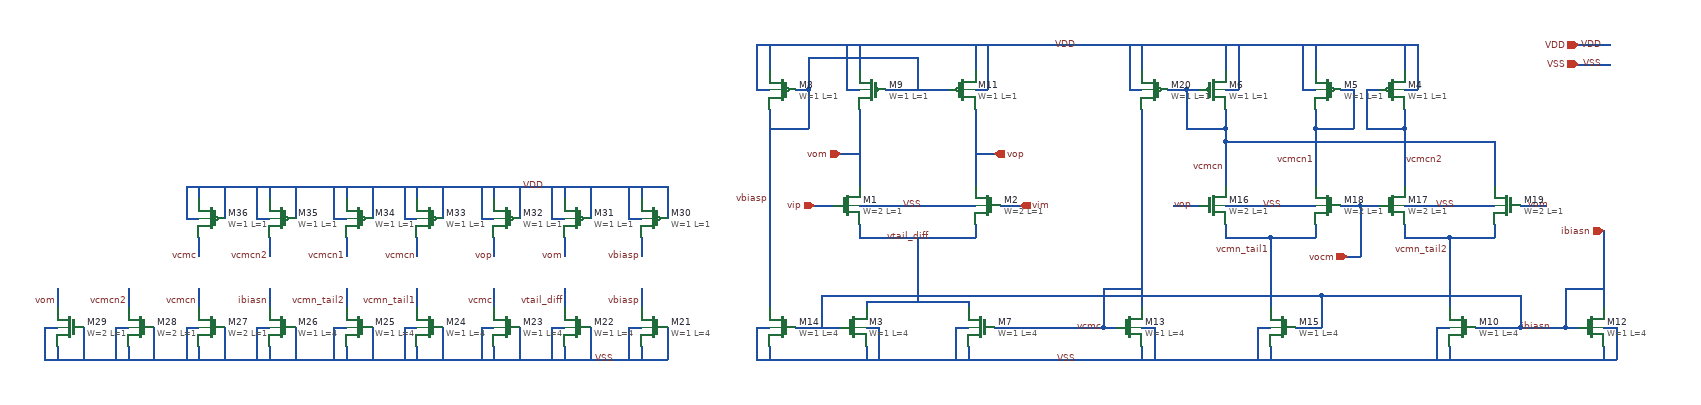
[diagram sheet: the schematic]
v {xschem version=2.9.9 file_version=1.2 

* Copyright 2020 Stefan Frederik Schippers
* 
* Licensed under the Apache License, Version 2.0 (the "License");
* you may not use this file except in compliance with the License.
* You may obtain a copy of the License at
*
*     https://www.apache.org/licenses/LICENSE-2.0
*
* Unless required by applicable law or agreed to in writing, software
* distributed under the License is distributed on an "AS IS" BASIS,
* WITHOUT WARRANTIES OR CONDITIONS OF ANY KIND, either express or implied.
* See the License for the specific language governing permissions and
* limitations under the License.

}
G {}
K {}
V {}
S {}
E {}
N -110 -220 -90 -220 { lab=VSS}
N -90 -220 -90 -170 { lab=VSS}
N 30 -220 50 -220 { lab=VSS}
N 30 -220 30 -170 { lab=VSS}
N -110 -260 -110 -250 { lab=vtail_diff}
N -110 -260 50 -260 { lab=vtail_diff}
N 50 -260 50 -250 { lab=vtail_diff}
N 50 -190 50 -170 { lab=VSS}
N -110 -190 -110 -170 { lab=VSS}
N -10 -410 60 -410 { lab=VSS}
N -120 -380 -120 -360 { lab=vtail_diff}
N -120 -360 60 -360 { lab=vtail_diff}
N 60 -380 60 -360 { lab=vtail_diff}
N 660 -410 690 -410 { lab=vocm}
N 520 -190 520 -170 { lab=VSS}
N 800 -190 800 -170 { lab=VSS}
N 450 -380 450 -360 { lab=vcmn_tail1}
N 520 -360 590 -360 { lab=vcmn_tail1}
N 590 -380 590 -360 { lab=vcmn_tail1}
N 730 -380 730 -360 { lab=vcmn_tail2}
N 800 -360 870 -360 { lab=vcmn_tail2}
N 870 -380 870 -360 { lab=vcmn_tail2}
N 670 -590 690 -590 { lab=vcmcn2}
N 670 -590 670 -530 { lab=vcmcn2}
N 670 -530 730 -530 { lab=vcmcn2}
N 390 -590 410 -590 { lab=vcmcn}
N 390 -590 390 -530 { lab=vcmcn}
N 390 -530 450 -530 { lab=vcmcn}
N 450 -510 450 -440 { lab=vcmcn}
N 450 -590 470 -590 { lab=VDD}
N 730 -590 750 -590 { lab=VDD}
N 450 -410 590 -410 { lab=VSS}
N 730 -410 870 -410 { lab=VSS}
N 780 -220 800 -220 { lab=VSS}
N 780 -220 780 -170 { lab=VSS}
N 500 -220 520 -220 { lab=VSS}
N 500 -220 500 -170 { lab=VSS}
N 1040 -190 1040 -170 { lab=VSS}
N 1040 -220 1060 -220 { lab=VSS}
N 1060 -220 1060 -170 { lab=VSS}
N 980 -220 1000 -220 { lab=ibiasn}
N 560 -220 600 -220 { lab=ibiasn}
N 600 -270 600 -220 { lab=ibiasn}
N 600 -270 910 -270 { lab=ibiasn}
N 910 -270 910 -220 { lab=ibiasn}
N 910 -410 950 -410 { lab=vom}
N 750 -660 750 -590 { lab=VDD}
N 730 -660 730 -620 { lab=VDD}
N 470 -660 470 -590 { lab=VDD}
N 450 -660 450 -620 { lab=VDD}
N 1040 -270 1040 -250 { lab=ibiasn}
N 800 -360 800 -250 { lab=vcmn_tail2}
N 520 -360 520 -250 { lab=vcmn_tail1}
N 320 -190 320 -170 { lab=VSS}
N 320 -220 340 -220 { lab=VSS}
N 340 -220 340 -170 { lab=VSS}
N 300 -590 320 -590 { lab=VDD}
N 320 -660 320 -620 { lab=VDD}
N 300 -660 300 -590 { lab=VDD}
N 630 -590 650 -590 { lab=vcmcn1}
N 650 -590 650 -530 { lab=vcmcn1}
N 590 -530 650 -530 { lab=vcmcn1}
N 570 -590 590 -590 { lab=VDD}
N 570 -660 570 -590 { lab=VDD}
N 590 -660 590 -620 { lab=VDD}
N 320 -560 320 -450 { lab=vcmc}
N 360 -590 390 -590 { lab=vcmcn}
N 730 -530 730 -440 { lab=vcmcn2}
N 590 -530 590 -440 { lab=vcmcn1}
N 870 -510 870 -440 { lab=vcmcn}
N 450 -510 870 -510 { lab=vcmcn}
N 640 -330 660 -330 { lab=vocm}
N 660 -410 660 -330 { lab=vocm}
N 730 -560 730 -530 { lab=vcmcn2}
N 450 -560 450 -530 { lab=vcmcn}
N 1040 -370 1040 -270 { lab=ibiasn}
N 910 -220 980 -220 { lab=ibiasn}
N 840 -220 910 -220 { lab=ibiasn}
N 730 -360 800 -360 { lab=vcmn_tail2}
N 450 -360 520 -360 { lab=vcmn_tail1}
N 590 -560 590 -530 { lab=vcmcn1}
N 450 -530 450 -510 { lab=vcmcn}
N -50 -410 -10 -410 { lab=VSS}
N -120 -410 -50 -410 { lab=VSS}
N 630 -410 660 -410 { lab=vocm}
N -190 -410 -160 -410 { lab=vip}
N 100 -410 130 -410 { lab=vim}
N -30 -360 -30 -340 { lab=vtail_diff}
N -30 -280 -30 -260 { lab=vtail_diff}
N -170 -220 -150 -220 { lab=ibiasn}
N 320 -390 320 -250 { lab=vcmc}
N 260 -280 260 -220 { lab=vcmc}
N 260 -280 320 -280 { lab=vcmc}
N 980 -280 980 -220 { lab=ibiasn}
N 980 -280 1040 -280 { lab=ibiasn}
N 60 -660 60 -620 { lab=VDD}
N 60 -590 80 -590 { lab=VDD}
N 80 -660 80 -590 { lab=VDD}
N -120 -660 -120 -620 { lab=VDD}
N -140 -590 -120 -590 { lab=VDD}
N -140 -660 -140 -590 { lab=VDD}
N -120 -560 -120 -440 { lab=vom}
N 60 -560 60 -440 { lab=vop}
N -150 -490 -120 -490 { lab=vom}
N 60 -490 90 -490 { lab=vop}
N 370 -410 410 -410 { lab=vop}
N 260 -220 280 -220 { lab=vcmc}
N 90 -220 110 -220 { lab=vcmc}
N -260 -190 -260 -170 { lab=VSS}
N -280 -220 -260 -220 { lab=VSS}
N -280 -220 -280 -170 { lab=VSS}
N -260 -660 -260 -620 { lab=VDD}
N -280 -590 -260 -590 { lab=VDD}
N -280 -660 -280 -590 { lab=VDD}
N -280 -170 1060 -170 { lab=VSS}
N -260 -560 -260 -250 { lab=vbiasp}
N -220 -220 -170 -220 { lab=ibiasn}
N -180 -270 600 -270 { lab=ibiasn}
N -180 -270 -180 -220 { lab=ibiasn}
N -220 -590 -200 -590 { lab=vbiasp}
N -200 -590 -200 -530 { lab=vbiasp}
N -260 -530 -200 -530 { lab=vbiasp}
N -200 -640 -200 -590 { lab=vbiasp}
N -200 -640 -30 -640 { lab=vbiasp}
N -30 -640 -30 -590 { lab=vbiasp}
N -80 -590 20 -590 { lab=vbiasp}
N 110 -220 260 -220 { lab=vcmc}
N -280 -660 750 -660 { lab=VDD}
N 1000 -660 1050 -660 { lab=VDD}
N 1000 -630 1050 -630 { lab=VSS}
N -30 -340 -30 -280 { lab=vtail_diff}
N 320 -450 320 -390 { lab=vcmc}
N -460 -190 -460 -170 { lab=VSS}
N -480 -220 -460 -220 { lab=VSS}
N -480 -220 -480 -170 { lab=VSS}
N -420 -220 -420 -170 { lab=VSS}
N -460 -280 -460 -250 { lab=vbiasp}
N -580 -190 -580 -170 { lab=VSS}
N -600 -220 -580 -220 { lab=VSS}
N -600 -220 -600 -170 { lab=VSS}
N -540 -220 -540 -170 { lab=VSS}
N -580 -280 -580 -250 { lab=vtail_diff}
N -690 -190 -690 -170 { lab=VSS}
N -710 -220 -690 -220 { lab=VSS}
N -710 -220 -710 -170 { lab=VSS}
N -650 -220 -650 -170 { lab=VSS}
N -690 -280 -690 -250 { lab=vcmc}
N -810 -190 -810 -170 { lab=VSS}
N -830 -220 -810 -220 { lab=VSS}
N -830 -220 -830 -170 { lab=VSS}
N -770 -220 -770 -170 { lab=VSS}
N -810 -280 -810 -250 { lab=vcmn_tail1}
N -920 -190 -920 -170 { lab=VSS}
N -940 -220 -920 -220 { lab=VSS}
N -940 -220 -940 -170 { lab=VSS}
N -880 -220 -880 -170 { lab=VSS}
N -920 -280 -920 -250 { lab=vcmn_tail2}
N -1040 -190 -1040 -170 { lab=VSS}
N -1060 -220 -1040 -220 { lab=VSS}
N -1060 -220 -1060 -170 { lab=VSS}
N -1000 -220 -1000 -170 { lab=VSS}
N -1040 -280 -1040 -250 { lab=ibiasn}
N -1150 -190 -1150 -170 { lab=VSS}
N -1170 -220 -1150 -220 { lab=VSS}
N -1170 -220 -1170 -170 { lab=VSS}
N -1110 -220 -1110 -170 { lab=VSS}
N -1150 -280 -1150 -250 { lab=vcmcn}
N -1260 -190 -1260 -170 { lab=VSS}
N -1280 -220 -1260 -220 { lab=VSS}
N -1280 -220 -1280 -170 { lab=VSS}
N -1220 -220 -1220 -170 { lab=VSS}
N -1260 -280 -1260 -250 { lab=vcmcn2}
N -1370 -190 -1370 -170 { lab=VSS}
N -1390 -220 -1370 -220 { lab=VSS}
N -1390 -220 -1390 -170 { lab=VSS}
N -1330 -220 -1330 -170 { lab=VSS}
N -1370 -280 -1370 -250 { lab=vom}
N -1390 -170 -420 -170 { lab=VSS}
N -460 -360 -460 -330 { lab=vbiasp}
N -420 -440 -420 -390 { lab=#net1}
N -460 -440 -460 -420 { lab=#net1}
N -480 -390 -460 -390 { lab=#net1}
N -480 -440 -480 -390 { lab=#net1}
N -580 -360 -580 -330 { lab=vom}
N -540 -440 -540 -390 { lab=#net1}
N -580 -440 -580 -420 { lab=#net1}
N -600 -390 -580 -390 { lab=#net1}
N -600 -440 -600 -390 { lab=#net1}
N -690 -360 -690 -330 { lab=vop}
N -650 -440 -650 -390 { lab=#net1}
N -690 -440 -690 -420 { lab=#net1}
N -710 -390 -690 -390 { lab=#net1}
N -710 -440 -710 -390 { lab=#net1}
N -810 -360 -810 -330 { lab=vcmcn}
N -770 -440 -770 -390 { lab=#net1}
N -810 -440 -810 -420 { lab=#net1}
N -830 -390 -810 -390 { lab=#net1}
N -830 -440 -830 -390 { lab=#net1}
N -920 -360 -920 -330 { lab=vcmcn1}
N -880 -440 -880 -390 { lab=#net1}
N -920 -440 -920 -420 { lab=#net1}
N -940 -390 -920 -390 { lab=#net1}
N -940 -440 -940 -390 { lab=#net1}
N -1040 -360 -1040 -330 { lab=vcmcn2}
N -1000 -440 -1000 -390 { lab=#net1}
N -1040 -440 -1040 -420 { lab=#net1}
N -1060 -390 -1040 -390 { lab=#net1}
N -1060 -440 -1060 -390 { lab=#net1}
N -1150 -360 -1150 -330 { lab=vcmc}
N -1110 -440 -1110 -390 { lab=#net1}
N -1150 -440 -1150 -420 { lab=#net1}
N -1170 -390 -1150 -390 { lab=#net1}
N -1170 -440 -1170 -390 { lab=#net1}
N -1170 -440 -420 -440 { lab=#net1}
C {devices/title.sym} 160 -30 0 0 {name=l1 author="Nikhil Poole"}
C {devices/lab_wire.sym} -10 -360 0 0 {name=l17 sig_type=std_logic lab=vtail_diff}
C {sky130_fd_pr/nfet_01v8.sym} 820 -220 0 1 {name=M10
L=4
W=1
nf=1
mult=1
ad="'int((nf+1)/2) * W/nf * 0.29'" 
pd="'2*int((nf+1)/2) * (W/nf + 0.29)'"
as="'int((nf+2)/2) * W/nf * 0.29'" 
ps="'2*int((nf+2)/2) * (W/nf + 0.29)'"
nrd="'0.29 / W'" nrs="'0.29 / W'"
sa=0 sb=0 sd=0
model=nfet_01v8
spiceprefix=X
}
C {sky130_fd_pr/nfet_01v8.sym} 1020 -220 0 0 {name=M12
L=4
W=1
nf=1
mult=10
ad="'int((nf+1)/2) * W/nf * 0.29'" 
pd="'2*int((nf+1)/2) * (W/nf + 0.29)'"
as="'int((nf+2)/2) * W/nf * 0.29'" 
ps="'2*int((nf+2)/2) * (W/nf + 0.29)'"
nrd="'0.29 / W'" nrs="'0.29 / W'"
sa=0 sb=0 sd=0
model=nfet_01v8
spiceprefix=X
}
C {devices/lab_wire.sym} 960 -220 0 0 {name=l63 sig_type=std_logic lab=ibiasn}
C {devices/lab_wire.sym} 590 -480 0 0 {name=l64 sig_type=std_logic lab=vcmcn1}
C {devices/lab_wire.sym} 450 -470 0 0 {name=l65 sig_type=std_logic lab=vcmcn}
C {devices/lab_wire.sym} 520 -340 0 0 {name=l66 sig_type=std_logic lab=vcmn_tail1}
C {devices/lab_wire.sym} 800 -340 0 0 {name=l67 sig_type=std_logic lab=vcmn_tail2}
C {devices/lab_wire.sym} 730 -480 0 1 {name=l68 sig_type=std_logic lab=vcmcn2}
C {devices/lab_wire.sym} 260 -220 0 0 {name=l70 sig_type=std_logic lab=vcmc}
C {devices/lab_wire.sym} 400 -410 0 0 {name=l71 sig_type=std_logic lab=vop}
C {devices/lab_wire.sym} 920 -410 0 1 {name=l72 sig_type=std_logic lab=vom}
C {devices/ipin.sym} -190 -410 0 0 {name=p3 lab=vip}
C {devices/ipin.sym} 130 -410 0 1 {name=p4 lab=vim}
C {devices/ipin.sym} 640 -330 0 0 {name=p5 lab=vocm}
C {devices/opin.sym} 90 -490 0 0 {name=p1 lab=vop}
C {devices/opin.sym} -150 -490 0 1 {name=p2 lab=vom}
C {sky130_fd_pr/pfet_01v8.sym} -240 -590 0 1 {name=M8
L=1
W=1
nf=1
mult=1
ad="'int((nf+1)/2) * W/nf * 0.29'" 
pd="'2*int((nf+1)/2) * (W/nf + 0.29)'"
as="'int((nf+2)/2) * W/nf * 0.29'" 
ps="'2*int((nf+2)/2) * (W/nf + 0.29)'"
nrd="'0.29 / W'" nrs="'0.29 / W'"
sa=0 sb=0 sd=0
model=pfet_01v8
spiceprefix=X
}
C {sky130_fd_pr/pfet_01v8.sym} -100 -590 0 1 {name=M9
L=1
W=1
nf=1
mult=1
ad="'int((nf+1)/2) * W/nf * 0.29'" 
pd="'2*int((nf+1)/2) * (W/nf + 0.29)'"
as="'int((nf+2)/2) * W/nf * 0.29'" 
ps="'2*int((nf+2)/2) * (W/nf + 0.29)'"
nrd="'0.29 / W'" nrs="'0.29 / W'"
sa=0 sb=0 sd=0
model=pfet_01v8
spiceprefix=X
}
C {sky130_fd_pr/pfet_01v8.sym} 40 -590 0 0 {name=M11
L=1
W=1
nf=1
mult=1
ad="'int((nf+1)/2) * W/nf * 0.29'" 
pd="'2*int((nf+1)/2) * (W/nf + 0.29)'"
as="'int((nf+2)/2) * W/nf * 0.29'" 
ps="'2*int((nf+2)/2) * (W/nf + 0.29)'"
nrd="'0.29 / W'" nrs="'0.29 / W'"
sa=0 sb=0 sd=0
model=pfet_01v8
spiceprefix=X
}
C {sky130_fd_pr/nfet_01v8.sym} 430 -410 0 0 {name=M16
L=1
W=2
nf=1
mult=4
ad="'int((nf+1)/2) * W/nf * 0.29'" 
pd="'2*int((nf+1)/2) * (W/nf + 0.29)'"
as="'int((nf+2)/2) * W/nf * 0.29'" 
ps="'2*int((nf+2)/2) * (W/nf + 0.29)'"
nrd="'0.29 / W'" nrs="'0.29 / W'"
sa=0 sb=0 sd=0
model=nfet_01v8
spiceprefix=X
}
C {sky130_fd_pr/nfet_01v8_lvt.sym} -140 -410 0 0 {name=M1
L=1
W=2
nf=1
mult=4
ad="'int((nf+1)/2) * W/nf * 0.29'" 
pd="'2*int((nf+1)/2) * (W/nf + 0.29)'"
as="'int((nf+2)/2) * W/nf * 0.29'" 
ps="'2*int((nf+2)/2) * (W/nf + 0.29)'"
nrd="'0.29 / W'" nrs="'0.29 / W'"
sa=0 sb=0 sd=0
model=nfet_01v8_lvt
spiceprefix=X
}
C {sky130_fd_pr/nfet_01v8_lvt.sym} 80 -410 0 1 {name=M2
L=1
W=2
nf=1
mult=4
ad="'int((nf+1)/2) * W/nf * 0.29'" 
pd="'2*int((nf+1)/2) * (W/nf + 0.29)'"
as="'int((nf+2)/2) * W/nf * 0.29'" 
ps="'2*int((nf+2)/2) * (W/nf + 0.29)'"
nrd="'0.29 / W'" nrs="'0.29 / W'"
sa=0 sb=0 sd=0
model=nfet_01v8_lvt
spiceprefix=X
}
C {devices/ipin.sym} 1040 -370 1 0 {name=p6 lab=ibiasn}
C {devices/lab_wire.sym} 220 -170 0 0 {name=l2 sig_type=std_logic lab=VSS}
C {devices/lab_wire.sym} 220 -660 0 0 {name=l3 sig_type=std_logic lab=VDD}
C {devices/lab_wire.sym} -20 -410 0 0 {name=l4 sig_type=std_logic lab=VSS}
C {devices/lab_wire.sym} 540 -410 0 0 {name=l5 sig_type=std_logic lab=VSS}
C {devices/lab_wire.sym} 810 -410 0 0 {name=l6 sig_type=std_logic lab=VSS}
C {devices/ipin.sym} 1000 -660 0 0 {name=p7 lab=VDD}
C {devices/ipin.sym} 1000 -630 0 0 {name=p8 lab=VSS}
C {devices/lab_wire.sym} 1040 -660 0 0 {name=l7 sig_type=std_logic lab=VDD}
C {devices/lab_wire.sym} 1040 -630 0 0 {name=l8 sig_type=std_logic lab=VSS}
C {devices/lab_wire.sym} -260 -420 0 0 {name=l9 sig_type=std_logic lab=vbiasp}
C {sky130_fd_pr/pfet_01v8.sym} 430 -590 0 0 {name=M6
L=1
W=1
nf=1
mult=1
ad="'int((nf+1)/2) * W/nf * 0.29'" 
pd="'2*int((nf+1)/2) * (W/nf + 0.29)'"
as="'int((nf+2)/2) * W/nf * 0.29'" 
ps="'2*int((nf+2)/2) * (W/nf + 0.29)'"
nrd="'0.29 / W'" nrs="'0.29 / W'"
sa=0 sb=0 sd=0
model=pfet_01v8
spiceprefix=X
}
C {sky130_fd_pr/pfet_01v8.sym} 340 -590 0 1 {name=M20
L=1
W=1
nf=1
mult=1
ad="'int((nf+1)/2) * W/nf * 0.29'" 
pd="'2*int((nf+1)/2) * (W/nf + 0.29)'"
as="'int((nf+2)/2) * W/nf * 0.29'" 
ps="'2*int((nf+2)/2) * (W/nf + 0.29)'"
nrd="'0.29 / W'" nrs="'0.29 / W'"
sa=0 sb=0 sd=0
model=pfet_01v8
spiceprefix=X
}
C {sky130_fd_pr/pfet_01v8.sym} 710 -590 0 0 {name=M4
L=1
W=1
nf=1
mult=1
ad="'int((nf+1)/2) * W/nf * 0.29'" 
pd="'2*int((nf+1)/2) * (W/nf + 0.29)'"
as="'int((nf+2)/2) * W/nf * 0.29'" 
ps="'2*int((nf+2)/2) * (W/nf + 0.29)'"
nrd="'0.29 / W'" nrs="'0.29 / W'"
sa=0 sb=0 sd=0
model=pfet_01v8
spiceprefix=X
}
C {sky130_fd_pr/pfet_01v8.sym} 610 -590 0 1 {name=M5
L=1
W=1
nf=1
mult=1
ad="'int((nf+1)/2) * W/nf * 0.29'" 
pd="'2*int((nf+1)/2) * (W/nf + 0.29)'"
as="'int((nf+2)/2) * W/nf * 0.29'" 
ps="'2*int((nf+2)/2) * (W/nf + 0.29)'"
nrd="'0.29 / W'" nrs="'0.29 / W'"
sa=0 sb=0 sd=0
model=pfet_01v8
spiceprefix=X
}
C {sky130_fd_pr/nfet_01v8.sym} 710 -410 0 0 {name=M17
L=1
W=2
nf=1
mult=4
ad="'int((nf+1)/2) * W/nf * 0.29'" 
pd="'2*int((nf+1)/2) * (W/nf + 0.29)'"
as="'int((nf+2)/2) * W/nf * 0.29'" 
ps="'2*int((nf+2)/2) * (W/nf + 0.29)'"
nrd="'0.29 / W'" nrs="'0.29 / W'"
sa=0 sb=0 sd=0
model=nfet_01v8
spiceprefix=X
}
C {sky130_fd_pr/nfet_01v8.sym} 610 -410 0 1 {name=M18
L=1
W=2
nf=1
mult=4
ad="'int((nf+1)/2) * W/nf * 0.29'" 
pd="'2*int((nf+1)/2) * (W/nf + 0.29)'"
as="'int((nf+2)/2) * W/nf * 0.29'" 
ps="'2*int((nf+2)/2) * (W/nf + 0.29)'"
nrd="'0.29 / W'" nrs="'0.29 / W'"
sa=0 sb=0 sd=0
model=nfet_01v8
spiceprefix=X
}
C {sky130_fd_pr/nfet_01v8.sym} 890 -410 0 1 {name=M19
L=1
W=2
nf=1
mult=4
ad="'int((nf+1)/2) * W/nf * 0.29'" 
pd="'2*int((nf+1)/2) * (W/nf + 0.29)'"
as="'int((nf+2)/2) * W/nf * 0.29'" 
ps="'2*int((nf+2)/2) * (W/nf + 0.29)'"
nrd="'0.29 / W'" nrs="'0.29 / W'"
sa=0 sb=0 sd=0
model=nfet_01v8
spiceprefix=X
}
C {sky130_fd_pr/nfet_01v8.sym} -130 -220 0 0 {name=M3
L=4
W=1
nf=1
mult=1
ad="'int((nf+1)/2) * W/nf * 0.29'" 
pd="'2*int((nf+1)/2) * (W/nf + 0.29)'"
as="'int((nf+2)/2) * W/nf * 0.29'" 
ps="'2*int((nf+2)/2) * (W/nf + 0.29)'"
nrd="'0.29 / W'" nrs="'0.29 / W'"
sa=0 sb=0 sd=0
model=nfet_01v8
spiceprefix=X
}
C {sky130_fd_pr/nfet_01v8.sym} 70 -220 0 1 {name=M7
L=4
W=1
nf=1
mult=1
ad="'int((nf+1)/2) * W/nf * 0.29'" 
pd="'2*int((nf+1)/2) * (W/nf + 0.29)'"
as="'int((nf+2)/2) * W/nf * 0.29'" 
ps="'2*int((nf+2)/2) * (W/nf + 0.29)'"
nrd="'0.29 / W'" nrs="'0.29 / W'"
sa=0 sb=0 sd=0
model=nfet_01v8
spiceprefix=X
}
C {sky130_fd_pr/nfet_01v8.sym} 300 -220 0 0 {name=M13
L=4
W=1
nf=1
mult=1
ad="'int((nf+1)/2) * W/nf * 0.29'" 
pd="'2*int((nf+1)/2) * (W/nf + 0.29)'"
as="'int((nf+2)/2) * W/nf * 0.29'" 
ps="'2*int((nf+2)/2) * (W/nf + 0.29)'"
nrd="'0.29 / W'" nrs="'0.29 / W'"
sa=0 sb=0 sd=0
model=nfet_01v8
spiceprefix=X
}
C {sky130_fd_pr/nfet_01v8.sym} -240 -220 0 1 {name=M14
L=4
W=1
nf=1
mult=1
ad="'int((nf+1)/2) * W/nf * 0.29'" 
pd="'2*int((nf+1)/2) * (W/nf + 0.29)'"
as="'int((nf+2)/2) * W/nf * 0.29'" 
ps="'2*int((nf+2)/2) * (W/nf + 0.29)'"
nrd="'0.29 / W'" nrs="'0.29 / W'"
sa=0 sb=0 sd=0
model=nfet_01v8
spiceprefix=X
}
C {sky130_fd_pr/nfet_01v8.sym} 540 -220 0 1 {name=M15
L=4
W=1
nf=1
mult=1
ad="'int((nf+1)/2) * W/nf * 0.29'" 
pd="'2*int((nf+1)/2) * (W/nf + 0.29)'"
as="'int((nf+2)/2) * W/nf * 0.29'" 
ps="'2*int((nf+2)/2) * (W/nf + 0.29)'"
nrd="'0.29 / W'" nrs="'0.29 / W'"
sa=0 sb=0 sd=0
model=nfet_01v8
spiceprefix=X
}
C {sky130_fd_pr/nfet_01v8.sym} -440 -220 0 1 {name=M21
L=4
W=1
nf=1
mult=1
ad="'int((nf+1)/2) * W/nf * 0.29'" 
pd="'2*int((nf+1)/2) * (W/nf + 0.29)'"
as="'int((nf+2)/2) * W/nf * 0.29'" 
ps="'2*int((nf+2)/2) * (W/nf + 0.29)'"
nrd="'0.29 / W'" nrs="'0.29 / W'"
sa=0 sb=0 sd=0
model=nfet_01v8
spiceprefix=X
}
C {devices/lab_wire.sym} -460 -260 0 0 {name=l10 sig_type=std_logic lab=vbiasp}
C {sky130_fd_pr/nfet_01v8.sym} -560 -220 0 1 {name=M22
L=4
W=1
nf=1
mult=2
ad="'int((nf+1)/2) * W/nf * 0.29'" 
pd="'2*int((nf+1)/2) * (W/nf + 0.29)'"
as="'int((nf+2)/2) * W/nf * 0.29'" 
ps="'2*int((nf+2)/2) * (W/nf + 0.29)'"
nrd="'0.29 / W'" nrs="'0.29 / W'"
sa=0 sb=0 sd=0
model=nfet_01v8
spiceprefix=X
}
C {devices/lab_wire.sym} -580 -260 0 0 {name=l11 sig_type=std_logic lab=vtail_diff}
C {sky130_fd_pr/nfet_01v8.sym} -670 -220 0 1 {name=M23
L=4
W=1
nf=1
mult=1
ad="'int((nf+1)/2) * W/nf * 0.29'" 
pd="'2*int((nf+1)/2) * (W/nf + 0.29)'"
as="'int((nf+2)/2) * W/nf * 0.29'" 
ps="'2*int((nf+2)/2) * (W/nf + 0.29)'"
nrd="'0.29 / W'" nrs="'0.29 / W'"
sa=0 sb=0 sd=0
model=nfet_01v8
spiceprefix=X
}
C {devices/lab_wire.sym} -690 -260 0 0 {name=l12 sig_type=std_logic lab=vcmc}
C {sky130_fd_pr/nfet_01v8.sym} -790 -220 0 1 {name=M24
L=4
W=1
nf=1
mult=1
ad="'int((nf+1)/2) * W/nf * 0.29'" 
pd="'2*int((nf+1)/2) * (W/nf + 0.29)'"
as="'int((nf+2)/2) * W/nf * 0.29'" 
ps="'2*int((nf+2)/2) * (W/nf + 0.29)'"
nrd="'0.29 / W'" nrs="'0.29 / W'"
sa=0 sb=0 sd=0
model=nfet_01v8
spiceprefix=X
}
C {devices/lab_wire.sym} -810 -260 0 0 {name=l13 sig_type=std_logic lab=vcmn_tail1}
C {sky130_fd_pr/nfet_01v8.sym} -900 -220 0 1 {name=M25
L=4
W=1
nf=1
mult=1
ad="'int((nf+1)/2) * W/nf * 0.29'" 
pd="'2*int((nf+1)/2) * (W/nf + 0.29)'"
as="'int((nf+2)/2) * W/nf * 0.29'" 
ps="'2*int((nf+2)/2) * (W/nf + 0.29)'"
nrd="'0.29 / W'" nrs="'0.29 / W'"
sa=0 sb=0 sd=0
model=nfet_01v8
spiceprefix=X
}
C {devices/lab_wire.sym} -920 -260 0 0 {name=l14 sig_type=std_logic lab=vcmn_tail2}
C {sky130_fd_pr/nfet_01v8.sym} -1020 -220 0 1 {name=M26
L=4
W=1
nf=1
mult=2
ad="'int((nf+1)/2) * W/nf * 0.29'" 
pd="'2*int((nf+1)/2) * (W/nf + 0.29)'"
as="'int((nf+2)/2) * W/nf * 0.29'" 
ps="'2*int((nf+2)/2) * (W/nf + 0.29)'"
nrd="'0.29 / W'" nrs="'0.29 / W'"
sa=0 sb=0 sd=0
model=nfet_01v8
spiceprefix=X
}
C {devices/lab_wire.sym} -1040 -260 0 0 {name=l15 sig_type=std_logic lab=ibiasn}
C {sky130_fd_pr/nfet_01v8.sym} -1130 -220 0 1 {name=M27
L=1
W=2
nf=1
mult=2
ad="'int((nf+1)/2) * W/nf * 0.29'" 
pd="'2*int((nf+1)/2) * (W/nf + 0.29)'"
as="'int((nf+2)/2) * W/nf * 0.29'" 
ps="'2*int((nf+2)/2) * (W/nf + 0.29)'"
nrd="'0.29 / W'" nrs="'0.29 / W'"
sa=0 sb=0 sd=0
model=nfet_01v8
spiceprefix=X
}
C {devices/lab_wire.sym} -1150 -260 0 0 {name=l16 sig_type=std_logic lab=vcmcn}
C {sky130_fd_pr/nfet_01v8.sym} -1240 -220 0 1 {name=M28
L=1
W=2
nf=1
mult=2
ad="'int((nf+1)/2) * W/nf * 0.29'" 
pd="'2*int((nf+1)/2) * (W/nf + 0.29)'"
as="'int((nf+2)/2) * W/nf * 0.29'" 
ps="'2*int((nf+2)/2) * (W/nf + 0.29)'"
nrd="'0.29 / W'" nrs="'0.29 / W'"
sa=0 sb=0 sd=0
model=nfet_01v8
spiceprefix=X
}
C {devices/lab_wire.sym} -1260 -260 0 0 {name=l18 sig_type=std_logic lab=vcmcn2}
C {devices/lab_wire.sym} -1370 -260 0 0 {name=l19 sig_type=std_logic lab=vom}
C {sky130_fd_pr/nfet_01v8_lvt.sym} -1350 -220 0 1 {name=M29
L=1
W=2
nf=1
mult=2
ad="'int((nf+1)/2) * W/nf * 0.29'" 
pd="'2*int((nf+1)/2) * (W/nf + 0.29)'"
as="'int((nf+2)/2) * W/nf * 0.29'" 
ps="'2*int((nf+2)/2) * (W/nf + 0.29)'"
nrd="'0.29 / W'" nrs="'0.29 / W'"
sa=0 sb=0 sd=0
model=nfet_01v8_lvt
spiceprefix=X
}
C {devices/lab_wire.sym} -500 -170 0 0 {name=l20 sig_type=std_logic lab=VSS}
C {sky130_fd_pr/pfet_01v8.sym} -440 -390 0 1 {name=M30
L=1
W=1
nf=1
mult=1
ad="'int((nf+1)/2) * W/nf * 0.29'" 
pd="'2*int((nf+1)/2) * (W/nf + 0.29)'"
as="'int((nf+2)/2) * W/nf * 0.29'" 
ps="'2*int((nf+2)/2) * (W/nf + 0.29)'"
nrd="'0.29 / W'" nrs="'0.29 / W'"
sa=0 sb=0 sd=0
model=pfet_01v8
spiceprefix=X
}
C {devices/lab_wire.sym} -460 -330 0 0 {name=l21 sig_type=std_logic lab=vbiasp}
C {sky130_fd_pr/pfet_01v8.sym} -560 -390 0 1 {name=M31
L=1
W=1
nf=1
mult=1
ad="'int((nf+1)/2) * W/nf * 0.29'" 
pd="'2*int((nf+1)/2) * (W/nf + 0.29)'"
as="'int((nf+2)/2) * W/nf * 0.29'" 
ps="'2*int((nf+2)/2) * (W/nf + 0.29)'"
nrd="'0.29 / W'" nrs="'0.29 / W'"
sa=0 sb=0 sd=0
model=pfet_01v8
spiceprefix=X
}
C {devices/lab_wire.sym} -580 -330 0 0 {name=l22 sig_type=std_logic lab=vom}
C {sky130_fd_pr/pfet_01v8.sym} -670 -390 0 1 {name=M32
L=1
W=1
nf=1
mult=1
ad="'int((nf+1)/2) * W/nf * 0.29'" 
pd="'2*int((nf+1)/2) * (W/nf + 0.29)'"
as="'int((nf+2)/2) * W/nf * 0.29'" 
ps="'2*int((nf+2)/2) * (W/nf + 0.29)'"
nrd="'0.29 / W'" nrs="'0.29 / W'"
sa=0 sb=0 sd=0
model=pfet_01v8
spiceprefix=X
}
C {devices/lab_wire.sym} -690 -330 0 0 {name=l23 sig_type=std_logic lab=vop}
C {sky130_fd_pr/pfet_01v8.sym} -790 -390 0 1 {name=M33
L=1
W=1
nf=1
mult=1
ad="'int((nf+1)/2) * W/nf * 0.29'" 
pd="'2*int((nf+1)/2) * (W/nf + 0.29)'"
as="'int((nf+2)/2) * W/nf * 0.29'" 
ps="'2*int((nf+2)/2) * (W/nf + 0.29)'"
nrd="'0.29 / W'" nrs="'0.29 / W'"
sa=0 sb=0 sd=0
model=pfet_01v8
spiceprefix=X
}
C {devices/lab_wire.sym} -810 -330 0 0 {name=l24 sig_type=std_logic lab=vcmcn}
C {sky130_fd_pr/pfet_01v8.sym} -900 -390 0 1 {name=M34
L=1
W=1
nf=1
mult=1
ad="'int((nf+1)/2) * W/nf * 0.29'" 
pd="'2*int((nf+1)/2) * (W/nf + 0.29)'"
as="'int((nf+2)/2) * W/nf * 0.29'" 
ps="'2*int((nf+2)/2) * (W/nf + 0.29)'"
nrd="'0.29 / W'" nrs="'0.29 / W'"
sa=0 sb=0 sd=0
model=pfet_01v8
spiceprefix=X
}
C {devices/lab_wire.sym} -920 -330 0 0 {name=l25 sig_type=std_logic lab=vcmcn1}
C {sky130_fd_pr/pfet_01v8.sym} -1020 -390 0 1 {name=M35
L=1
W=1
nf=1
mult=1
ad="'int((nf+1)/2) * W/nf * 0.29'" 
pd="'2*int((nf+1)/2) * (W/nf + 0.29)'"
as="'int((nf+2)/2) * W/nf * 0.29'" 
ps="'2*int((nf+2)/2) * (W/nf + 0.29)'"
nrd="'0.29 / W'" nrs="'0.29 / W'"
sa=0 sb=0 sd=0
model=pfet_01v8
spiceprefix=X
}
C {devices/lab_wire.sym} -1040 -330 0 0 {name=l26 sig_type=std_logic lab=vcmcn2}
C {sky130_fd_pr/pfet_01v8.sym} -1130 -390 0 1 {name=M36
L=1
W=1
nf=1
mult=1
ad="'int((nf+1)/2) * W/nf * 0.29'" 
pd="'2*int((nf+1)/2) * (W/nf + 0.29)'"
as="'int((nf+2)/2) * W/nf * 0.29'" 
ps="'2*int((nf+2)/2) * (W/nf + 0.29)'"
nrd="'0.29 / W'" nrs="'0.29 / W'"
sa=0 sb=0 sd=0
model=pfet_01v8
spiceprefix=X
}
C {devices/lab_wire.sym} -1150 -330 0 0 {name=l27 sig_type=std_logic lab=vcmc}
C {devices/lab_wire.sym} -610 -440 0 0 {name=l28 sig_type=std_logic lab=VDD}
